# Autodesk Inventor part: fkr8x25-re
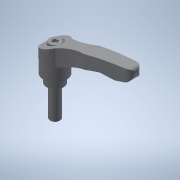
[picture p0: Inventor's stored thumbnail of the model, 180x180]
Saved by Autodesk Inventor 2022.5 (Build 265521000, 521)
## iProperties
Created: 2017-09
Part Number: fkr8x25-re
Material: 一般
Document SubType Name: Modeling
Designer: imaocorp
Density: 1 g/cm^3
Appearance: 既定
Author: imaocorp
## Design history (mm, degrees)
node "fkr8x25-re.x_t1"
node "fkr8x25-re"
node "Base1"
